########################################################################
#
# Copyright 2025 IHP PDK Authors
# 
# Licensed under the Apache License, Version 2.0 (the "License");
# you may not use this file except in compliance with the License.
# You may obtain a copy of the License at
# 
#    https://www.apache.org/licenses/LICENSE-2.0
# 
# Unless required by applicable law or agreed to in writing, software
# distributed under the License is distributed on an "AS IS" BASIS,
# WITHOUT WARRANTIES OR CONDITIONS OF ANY KIND, either express or implied.
# See the License for the specific language governing permissions and
# limitations under the License.
#
########################################################################

VERSION 5.7 ;
BUSBITCHARS "[]" ;
DIVIDERCHAR "/" ;

PROPERTYDEFINITIONS
  MACRO CatenaDesignType STRING ;
END PROPERTYDEFINITIONS

SITE  CoreSite
    CLASS       CORE ;
    SYMMETRY    Y ;
    SIZE        0.48 BY 3.78 ;
END  CoreSite

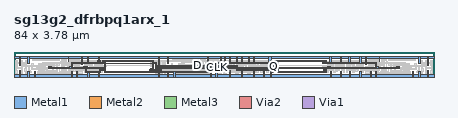
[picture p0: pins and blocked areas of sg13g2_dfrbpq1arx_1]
MACRO sg13g2_dfrbpq1arx_1
  CLASS CORE ;
  ORIGIN 0 0 ;
  FOREIGN sg13g2_dfrbpq1arx_1 0 0 ;
  SIZE 84 BY 3.78 ;
  SYMMETRY X Y ;
  SITE CoreSite ;
  PIN RESET_B
    DIRECTION INPUT ;
    USE SIGNAL ;
    ANTENNAPARTIALMETALAREA 7.2588 LAYER Metal3 ;
    ANTENNAPARTIALMETALAREA 0.605 LAYER Metal2 ;
    ANTENNAPARTIALCUTAREA 0.1444 LAYER Via1 ;
    ANTENNAPARTIALCUTAREA 0.1444 LAYER Via2 ;
    ANTENNAMODEL OXIDE1 ;
      ANTENNAGATEAREA 0.3276 LAYER Metal2 ;
      ANTENNAGATEAREA 0.3276 LAYER Metal1 ;
      ANTENNAGATEAREA 0.9828 LAYER Metal3 ;
      ANTENNAMAXAREACAR 12.730998 LAYER Metal3 ;
      ANTENNAMAXAREACAR 4.612561 LAYER Metal2 ;
      ANTENNAMAXCUTCAR 0.110195 LAYER Via1 ;
      ANTENNAMAXCUTCAR 0.550977 LAYER Via2 ;
    PORT
      LAYER Metal1 ;
        RECT 72.225 1.51 72.83 1.965 ;
        RECT 61.82 2.795 62.44 3.085 ;
        RECT 52.215 2.86 62.44 3.02 ;
        RECT 52.215 2.34 52.425 3.04 ;
        RECT 39.01 1.51 39.615 1.965 ;
        RECT 27.735 0.74 27.945 1.44 ;
        RECT 18.095 2.44 27.92 2.6 ;
        RECT 27.76 0.74 27.92 2.6 ;
        RECT 18.095 2.415 18.385 2.625 ;
        RECT 11.17 1.51 11.775 1.965 ;
      LAYER Metal2 ;
        RECT 71.88 2.42 72.58 2.62 ;
        RECT 72.38 1.535 72.58 2.62 ;
        RECT 61.82 2.795 62.44 3.085 ;
        RECT 61.775 2.42 62.065 3.04 ;
        RECT 52.22 2.34 52.42 3.04 ;
        RECT 51.72 2.42 52.42 2.62 ;
        RECT 39.26 2.42 39.96 2.62 ;
        RECT 39.26 0.74 39.46 2.62 ;
        RECT 38.76 0.74 39.46 0.94 ;
        RECT 27.74 0.74 28.44 0.94 ;
        RECT 27.74 0.74 27.94 1.44 ;
        RECT 17.18 2.42 18.385 2.62 ;
        RECT 16.7 2.84 17.38 3.04 ;
        RECT 17.18 2.42 17.38 3.04 ;
        RECT 16.7 2.42 16.9 3.04 ;
        RECT 16.2 2.42 16.9 2.62 ;
        RECT 11.42 2.42 12.12 2.62 ;
        RECT 11.42 1.535 11.62 2.62 ;
      LAYER Metal3 ;
        RECT 61.775 2.42 72.58 2.62 ;
        RECT 61.775 2.42 62.065 3.04 ;
        RECT 39.26 2.42 52.42 2.62 ;
        RECT 27.74 0.74 39.46 0.94 ;
        RECT 11.42 2.42 16.9 2.62 ;
      LAYER Via2 ;
        RECT 11.47 2.425 11.66 2.615 ;
        RECT 11.88 2.425 12.07 2.615 ;
        RECT 16.25 2.425 16.44 2.615 ;
        RECT 16.66 2.425 16.85 2.615 ;
        RECT 27.79 0.745 27.98 0.935 ;
        RECT 28.2 0.745 28.39 0.935 ;
        RECT 38.81 0.745 39 0.935 ;
        RECT 39.22 0.745 39.41 0.935 ;
        RECT 39.31 2.425 39.5 2.615 ;
        RECT 39.72 2.425 39.91 2.615 ;
        RECT 51.77 2.425 51.96 2.615 ;
        RECT 52.18 2.425 52.37 2.615 ;
        RECT 61.825 2.84 62.015 3.03 ;
        RECT 61.825 2.43 62.015 2.62 ;
        RECT 71.93 2.425 72.12 2.615 ;
        RECT 72.34 2.425 72.53 2.615 ;
      LAYER Via1 ;
        RECT 11.425 1.585 11.615 1.775 ;
        RECT 18.145 2.425 18.335 2.615 ;
        RECT 27.745 1.2 27.935 1.39 ;
        RECT 27.745 0.79 27.935 0.98 ;
        RECT 39.265 1.585 39.455 1.775 ;
        RECT 52.225 2.8 52.415 2.99 ;
        RECT 52.225 2.39 52.415 2.58 ;
        RECT 61.83 2.845 62.02 3.035 ;
        RECT 62.24 2.845 62.43 3.035 ;
        RECT 72.385 1.585 72.575 1.775 ;
    END
  END RESET_B
  PIN CLK
    DIRECTION INPUT ;
    USE SIGNAL ;
    ANTENNAPARTIALMETALAREA 8.124 LAYER Metal3 ;
    ANTENNAPARTIALMETALAREA 0.504 LAYER Metal2 ;
    ANTENNAPARTIALCUTAREA 0.1444 LAYER Via1 ;
    ANTENNAPARTIALCUTAREA 0.1444 LAYER Via2 ;
    ANTENNAMODEL OXIDE1 ;
      ANTENNAGATEAREA 0.2418 LAYER Metal2 ;
      ANTENNAGATEAREA 0.2418 LAYER Metal1 ;
      ANTENNAGATEAREA 0.7254 LAYER Metal3 ;
      ANTENNAMAXAREACAR 12.567411 LAYER Metal3 ;
      ANTENNAMAXAREACAR 0.74359 LAYER Metal2 ;
      ANTENNAMAXCUTCAR 0.149297 LAYER Via1 ;
      ANTENNAMAXCUTCAR 0.447891 LAYER Via2 ;
    PORT
      LAYER Metal1 ;
        RECT 76.53 1.52 77.07 1.84 ;
        RECT 61.815 0.7 62.025 1.4 ;
        RECT 52.695 0.76 62.025 0.92 ;
        RECT 52.695 0.7 52.905 1.4 ;
        RECT 34.77 1.52 35.31 1.84 ;
        RECT 27.695 2.835 27.985 3.045 ;
        RECT 18.14 2.86 27.985 3.02 ;
        RECT 18.14 2.86 18.43 3.09 ;
        RECT 6.93 1.52 7.47 1.84 ;
      LAYER Metal2 ;
        RECT 76.7 1.535 76.9 1.825 ;
        RECT 76.2 1.58 76.9 1.78 ;
        RECT 62.3 1.58 63 1.78 ;
        RECT 62.3 0.74 62.5 1.78 ;
        RECT 61.82 0.74 62.5 0.94 ;
        RECT 61.82 0.7 62.02 1.4 ;
        RECT 52.7 0.685 52.9 1.44 ;
        RECT 34.94 1.58 35.64 1.78 ;
        RECT 34.94 1.535 35.14 1.825 ;
        RECT 27.74 2.42 28.42 2.62 ;
        RECT 28.22 1.58 28.42 2.62 ;
        RECT 27.74 2.42 27.94 3.085 ;
        RECT 18.14 2.84 18.39 3.13 ;
        RECT 17.64 2.84 18.39 3.04 ;
        RECT 7.1 1.58 7.8 1.78 ;
        RECT 7.1 1.535 7.3 1.825 ;
      LAYER Metal3 ;
        RECT 62.3 1.58 76.9 1.78 ;
        RECT 28.22 1.58 52.9 1.78 ;
        RECT 52.7 0.74 52.9 1.78 ;
        RECT 28.22 1.58 28.42 2.28 ;
        RECT 17.64 2.84 18.34 3.04 ;
        RECT 18.14 1.58 18.34 3.04 ;
        RECT 7.1 1.58 18.34 1.78 ;
      LAYER Via2 ;
        RECT 7.15 1.585 7.34 1.775 ;
        RECT 7.56 1.585 7.75 1.775 ;
        RECT 17.69 2.845 17.88 3.035 ;
        RECT 18.1 2.845 18.29 3.035 ;
        RECT 28.225 2.04 28.415 2.23 ;
        RECT 28.225 1.63 28.415 1.82 ;
        RECT 34.99 1.585 35.18 1.775 ;
        RECT 35.4 1.585 35.59 1.775 ;
        RECT 52.705 1.2 52.895 1.39 ;
        RECT 52.705 0.79 52.895 0.98 ;
        RECT 62.35 1.585 62.54 1.775 ;
        RECT 62.76 1.585 62.95 1.775 ;
        RECT 76.25 1.585 76.44 1.775 ;
        RECT 76.66 1.585 76.85 1.775 ;
      LAYER Via1 ;
        RECT 7.105 1.585 7.295 1.775 ;
        RECT 18.19 2.89 18.38 3.08 ;
        RECT 27.745 2.845 27.935 3.035 ;
        RECT 34.945 1.585 35.135 1.775 ;
        RECT 52.705 1.16 52.895 1.35 ;
        RECT 52.705 0.75 52.895 0.94 ;
        RECT 61.825 1.16 62.015 1.35 ;
        RECT 61.825 0.75 62.015 0.94 ;
        RECT 76.705 1.585 76.895 1.775 ;
    END
  END CLK
  PIN VSS
    DIRECTION INOUT ;
    USE GROUND ;
    SHAPE ABUTMENT ;
    NETEXPR "VSS VSS!" ;
    PORT
      LAYER Metal1 ;
        RECT 0 -0.22 84 0.22 ;
        RECT 82.715 -0.22 82.975 1.19 ;
        RECT 80.99 -0.22 81.23 0.85 ;
        RECT 79.64 -0.22 79.9 0.85 ;
        RECT 72.315 -0.22 72.575 0.915 ;
        RECT 71.22 -0.22 71.49 0.85 ;
        RECT 69.155 -0.22 69.415 0.87 ;
        RECT 67.1 -0.22 67.36 0.87 ;
        RECT 65.315 -0.22 65.575 0.87 ;
        RECT 63.26 -0.22 63.52 0.87 ;
        RECT 51.215 -0.22 51.475 0.87 ;
        RECT 49.855 -0.22 50.115 0.87 ;
        RECT 47.825 -0.22 48.085 1.155 ;
        RECT 45.425 -0.22 45.685 1.155 ;
        RECT 43.025 -0.22 43.285 1.155 ;
        RECT 40.35 -0.22 40.62 0.85 ;
        RECT 39.265 -0.22 39.525 0.915 ;
        RECT 31.94 -0.22 32.2 0.85 ;
        RECT 30.61 -0.22 30.85 0.85 ;
        RECT 28.865 -0.22 29.125 1.19 ;
        RECT 16.835 -0.22 17.095 0.87 ;
        RECT 14.78 -0.22 15.04 0.87 ;
        RECT 12.51 -0.22 12.78 0.85 ;
        RECT 11.425 -0.22 11.685 0.915 ;
        RECT 4.1 -0.22 4.36 0.85 ;
        RECT 2.77 -0.22 3.01 0.85 ;
        RECT 1.025 -0.22 1.285 1.19 ;
    END
  END VSS
  PIN VDD
    DIRECTION INOUT ;
    USE POWER ;
    SHAPE ABUTMENT ;
    NETEXPR "VDD VDD!" ;
    PORT
      LAYER Metal1 ;
        RECT 0 3.56 84 4 ;
        RECT 82.71 2.1 82.98 4 ;
        RECT 80.97 2.46 81.23 4 ;
        RECT 73.025 2.86 73.195 4 ;
        RECT 70.295 2.24 70.555 4 ;
        RECT 69.14 2.455 69.4 4 ;
        RECT 66.985 2.65 67.25 4 ;
        RECT 65.3 2.455 65.56 4 ;
        RECT 63.145 2.65 63.41 4 ;
        RECT 50.81 2.475 51.41 4 ;
        RECT 47.825 2.56 48.085 4 ;
        RECT 46.805 2.56 47.065 4 ;
        RECT 45.425 2.56 45.685 4 ;
        RECT 44.405 2.56 44.665 4 ;
        RECT 43.025 2.56 43.285 4 ;
        RECT 42.005 2.56 42.265 4 ;
        RECT 41.285 2.24 41.545 4 ;
        RECT 38.645 2.86 38.815 4 ;
        RECT 30.61 2.46 30.87 4 ;
        RECT 28.86 2.1 29.13 4 ;
        RECT 16.82 2.455 17.08 4 ;
        RECT 14.665 2.65 14.93 4 ;
        RECT 13.445 2.24 13.705 4 ;
        RECT 10.805 2.86 10.975 4 ;
        RECT 2.77 2.46 3.03 4 ;
        RECT 1.02 2.1 1.29 4 ;
    END
  END VDD
  PIN D
    DIRECTION INPUT ;
    USE SIGNAL ;
    ANTENNAPARTIALMETALAREA 5.597 LAYER Metal3 ;
    ANTENNAPARTIALCUTAREA 0.1444 LAYER Via1 ;
    ANTENNAPARTIALCUTAREA 0.1444 LAYER Via2 ;
    ANTENNAMODEL OXIDE1 ;
      ANTENNAGATEAREA 0.1092 LAYER Metal2 ;
      ANTENNAGATEAREA 0.1092 LAYER Metal1 ;
      ANTENNAGATEAREA 0.3276 LAYER Metal3 ;
      ANTENNAMAXAREACAR 39.387057 LAYER Metal3 ;
      ANTENNAMAXAREACAR 18.283883 LAYER Metal2 ;
      ANTENNAMAXCUTCAR 0.661172 LAYER Via1 ;
      ANTENNAMAXCUTCAR 1.322344 LAYER Via2 ;
    PORT
      LAYER Metal1 ;
        RECT 62.605 1.425 63.235 1.945 ;
        RECT 52.215 1.6 63.235 1.76 ;
        RECT 52.215 1.08 52.425 1.78 ;
        RECT 41.16 1.07 41.505 1.89 ;
        RECT 27.17 0.74 27.46 1.36 ;
        RECT 18.135 0.76 27.46 0.92 ;
        RECT 18.135 0.74 18.345 1.44 ;
        RECT 14.125 1.425 14.755 1.945 ;
        RECT 13.88 1.535 14.755 1.825 ;
      LAYER Metal2 ;
        RECT 52.22 1.08 52.42 1.78 ;
        RECT 51.26 1.16 52.42 1.36 ;
        RECT 44.495 1.16 44.785 1.36 ;
        RECT 44.04 2 44.74 2.2 ;
        RECT 44.54 1.16 44.74 2.2 ;
        RECT 41.18 2 41.88 2.2 ;
        RECT 41.18 1.16 41.38 2.2 ;
        RECT 28.7 2 29.4 2.2 ;
        RECT 28.7 1.16 29.4 1.36 ;
        RECT 28.7 1.16 28.9 2.2 ;
        RECT 27.26 0.66 27.46 1.415 ;
        RECT 27.21 0.7 27.46 1.4 ;
        RECT 17.66 1.16 18.36 1.36 ;
        RECT 18.14 0.74 18.34 1.44 ;
        RECT 14.3 0.74 15 0.94 ;
        RECT 13.88 1.535 14.5 1.825 ;
        RECT 14.3 0.74 14.5 1.825 ;
      LAYER Metal3 ;
        RECT 44.495 1.16 51.96 1.36 ;
        RECT 28.7 2 44.74 2.2 ;
        RECT 27.26 1.16 29.4 1.36 ;
        RECT 27.26 0.66 27.46 1.36 ;
        RECT 17.18 1.16 18.36 1.36 ;
        RECT 17.18 0.74 17.38 1.36 ;
        RECT 14.3 0.74 17.38 0.94 ;
      LAYER Via2 ;
        RECT 14.35 0.745 14.54 0.935 ;
        RECT 14.76 0.745 14.95 0.935 ;
        RECT 17.71 1.165 17.9 1.355 ;
        RECT 18.12 1.165 18.31 1.355 ;
        RECT 27.265 1.12 27.455 1.31 ;
        RECT 27.265 0.71 27.455 0.9 ;
        RECT 28.75 2.005 28.94 2.195 ;
        RECT 28.75 1.165 28.94 1.355 ;
        RECT 29.16 2.005 29.35 2.195 ;
        RECT 29.16 1.165 29.35 1.355 ;
        RECT 41.23 2.005 41.42 2.195 ;
        RECT 41.64 2.005 41.83 2.195 ;
        RECT 44.09 2.005 44.28 2.195 ;
        RECT 44.5 2.005 44.69 2.195 ;
        RECT 44.545 1.165 44.735 1.355 ;
        RECT 51.31 1.165 51.5 1.355 ;
        RECT 51.72 1.165 51.91 1.355 ;
      LAYER Via1 ;
        RECT 13.89 1.585 14.08 1.775 ;
        RECT 14.3 1.585 14.49 1.775 ;
        RECT 18.145 1.2 18.335 1.39 ;
        RECT 18.145 0.79 18.335 0.98 ;
        RECT 27.22 1.16 27.41 1.35 ;
        RECT 27.22 0.75 27.41 0.94 ;
        RECT 41.185 1.62 41.375 1.81 ;
        RECT 41.185 1.21 41.375 1.4 ;
        RECT 52.225 1.54 52.415 1.73 ;
        RECT 52.225 1.13 52.415 1.32 ;
    END
  END D
  PIN Q
    DIRECTION OUTPUT ;
    USE SIGNAL ;
    ANTENNAPARTIALCUTAREA 0.0361 LAYER Via1 ;
    ANTENNAPARTIALCUTAREA 0.0722 LAYER Via2 ;
    ANTENNADIFFAREA 0.6324 LAYER Metal2 ;
    ANTENNADIFFAREA 0.6324 LAYER Metal1 ;
    ANTENNADIFFAREA 0.6324 LAYER Metal3 ;
    PORT
      LAYER Metal1 ;
        RECT 51.65 2.86 52.01 3.16 ;
        RECT 51.85 0.605 52.01 3.16 ;
        RECT 51.66 2.22 52.01 3.16 ;
        RECT 51.72 0.605 52.01 1.215 ;
      LAYER Metal2 ;
        RECT 51.26 2.84 51.96 3.04 ;
        RECT 51.69 2.84 51.94 3.13 ;
      LAYER Metal3 ;
        RECT 51.26 2.84 52.46 3.04 ;
      LAYER Via2 ;
        RECT 51.31 2.845 51.5 3.035 ;
        RECT 51.72 2.845 51.91 3.035 ;
      LAYER Via1 ;
        RECT 51.7 2.89 51.89 3.08 ;
    END
  END Q
  OBS
    LAYER Metal1 ;
      RECT 83.225 2.095 83.64 3.155 ;
      RECT 83.43 0.59 83.64 3.155 ;
      RECT 83.415 1.92 83.64 3.155 ;
      RECT 83.205 0.59 83.64 1.19 ;
      RECT 82.205 0.59 82.465 3.155 ;
      RECT 82.95 1.445 83.25 1.745 ;
      RECT 82.205 1.485 83.25 1.71 ;
      RECT 81.48 0.59 81.74 3.155 ;
      RECT 81.42 0.99 81.805 1.52 ;
      RECT 80.15 2.035 80.41 2.495 ;
      RECT 79.3 2.035 81.08 2.195 ;
      RECT 80.92 1.03 81.08 2.195 ;
      RECT 79.3 1.69 79.56 2.195 ;
      RECT 80.65 1.03 81.08 1.19 ;
      RECT 80.65 0.625 80.81 1.19 ;
      RECT 80.46 0.625 80.81 0.885 ;
      RECT 78.555 2.225 79.03 2.485 ;
      RECT 78.87 1.145 79.03 2.485 ;
      RECT 80.245 1.35 80.55 1.625 ;
      RECT 78.87 1.35 80.55 1.51 ;
      RECT 78.87 1.145 79.05 1.51 ;
      RECT 78.04 1.145 79.05 1.315 ;
      RECT 79.99 3.025 80.24 3.285 ;
      RECT 74.935 3.025 75.195 3.285 ;
      RECT 74.935 3.075 80.24 3.235 ;
      RECT 77.59 0.805 77.805 1.31 ;
      RECT 77.59 0.805 79.39 0.965 ;
      RECT 79.13 0.59 79.39 0.965 ;
      RECT 71.28 2.5 72.02 2.76 ;
      RECT 71.28 1.15 71.44 2.76 ;
      RECT 77.825 1.555 78.015 2.425 ;
      RECT 73.03 1.705 73.29 1.965 ;
      RECT 77.25 1.555 78.015 1.725 ;
      RECT 73.03 1.15 73.19 1.965 ;
      RECT 77.25 0.44 77.41 1.725 ;
      RECT 71.28 1.15 73.19 1.31 ;
      RECT 72.785 0.44 72.955 1.31 ;
      RECT 71.8 0.815 72.06 1.31 ;
      RECT 78.62 0.44 78.88 0.625 ;
      RECT 72.785 0.44 78.88 0.605 ;
      RECT 75.63 2.63 78.355 2.8 ;
      RECT 78.195 1.525 78.355 2.8 ;
      RECT 75.63 2.07 75.89 2.8 ;
      RECT 74.935 2.16 75.89 2.42 ;
      RECT 75.225 2.07 75.89 2.42 ;
      RECT 75.225 0.92 75.5 2.42 ;
      RECT 78.195 1.525 78.68 1.785 ;
      RECT 75.225 0.92 75.895 1.18 ;
      RECT 76.1 2.07 77.605 2.33 ;
      RECT 76.1 0.98 76.26 2.33 ;
      RECT 75.805 1.575 76.26 1.835 ;
      RECT 76.835 0.92 77.07 1.18 ;
      RECT 76.1 0.98 77.07 1.14 ;
      RECT 74.74 1.44 74.985 1.7 ;
      RECT 74.805 0.785 74.985 1.7 ;
      RECT 73.2 0.785 74.985 0.96 ;
      RECT 73.445 3.08 74.585 3.24 ;
      RECT 74.4 2.655 74.585 3.24 ;
      RECT 70.865 3.08 72.845 3.24 ;
      RECT 72.685 2.52 72.845 3.24 ;
      RECT 73.445 2.52 73.615 3.24 ;
      RECT 70.865 0.59 71.03 3.24 ;
      RECT 74.4 2.655 74.745 2.915 ;
      RECT 72.685 2.52 73.615 2.68 ;
      RECT 74.4 1.16 74.56 3.24 ;
      RECT 70.8 2.24 71.06 2.5 ;
      RECT 73.465 1.16 73.725 1.64 ;
      RECT 73.465 1.16 74.56 1.32 ;
      RECT 70.29 0.59 71.03 0.85 ;
      RECT 72.325 2.145 72.505 2.9 ;
      RECT 73.975 1.5 74.195 2.805 ;
      RECT 72.325 2.145 74.195 2.315 ;
      RECT 71.665 2.145 74.195 2.305 ;
      RECT 71.665 1.705 71.925 2.305 ;
      RECT 69.67 2.22 69.925 3.16 ;
      RECT 69.735 0.61 69.925 3.16 ;
      RECT 70.335 1.07 70.68 1.89 ;
      RECT 69.305 1.115 69.925 1.37 ;
      RECT 69.665 0.61 69.925 1.37 ;
      RECT 69.305 1.18 70.68 1.34 ;
      RECT 68.405 2.03 68.665 3.04 ;
      RECT 68.405 2.03 69.445 2.205 ;
      RECT 69.285 1.55 69.445 2.205 ;
      RECT 68.82 1.55 69.555 1.81 ;
      RECT 68.82 1.16 68.98 1.81 ;
      RECT 68.395 1.16 68.98 1.36 ;
      RECT 68.395 0.96 68.635 1.36 ;
      RECT 67.76 2.615 68.065 2.945 ;
      RECT 67.82 1.555 68.065 2.945 ;
      RECT 67.82 1.555 68.64 1.815 ;
      RECT 67.82 0.61 68.05 2.945 ;
      RECT 67.76 0.61 68.05 0.87 ;
      RECT 66.48 2.195 66.74 2.91 ;
      RECT 66.48 2.195 67.615 2.4 ;
      RECT 67.36 1.065 67.615 2.4 ;
      RECT 66.45 1.065 67.615 1.24 ;
      RECT 66.45 0.61 66.72 1.24 ;
      RECT 65.83 2.22 66.085 3.16 ;
      RECT 65.895 0.61 66.085 3.16 ;
      RECT 65.465 1.115 66.085 1.37 ;
      RECT 65.825 0.61 66.085 1.37 ;
      RECT 64.565 2.03 64.825 3.04 ;
      RECT 64.565 2.03 65.605 2.205 ;
      RECT 65.445 1.55 65.605 2.205 ;
      RECT 64.98 1.55 65.715 1.81 ;
      RECT 64.98 1.16 65.14 1.81 ;
      RECT 64.555 1.16 65.14 1.36 ;
      RECT 64.555 0.96 64.795 1.36 ;
      RECT 63.92 2.615 64.225 2.945 ;
      RECT 63.98 1.555 64.225 2.945 ;
      RECT 63.98 1.555 64.8 1.815 ;
      RECT 63.98 0.61 64.21 2.945 ;
      RECT 63.92 0.61 64.21 0.87 ;
      RECT 62.64 2.195 62.9 2.91 ;
      RECT 62.64 2.195 63.775 2.4 ;
      RECT 63.52 1.065 63.775 2.4 ;
      RECT 62.61 1.065 63.775 1.24 ;
      RECT 62.61 0.61 62.88 1.24 ;
      RECT 52.695 1.96 52.905 2.66 ;
      RECT 52.695 2.02 62.02 2.18 ;
      RECT 61.73 1.95 62.02 2.18 ;
      RECT 49.345 2.09 49.605 3.04 ;
      RECT 49.345 2.09 51.475 2.295 ;
      RECT 51.305 1.115 51.475 2.295 ;
      RECT 51.305 1.52 51.67 1.85 ;
      RECT 49.345 1.115 51.475 1.325 ;
      RECT 49.345 1.11 50.925 1.325 ;
      RECT 50.405 0.61 50.925 1.325 ;
      RECT 49.345 0.61 49.605 1.325 ;
      RECT 48.335 2.14 48.835 3.16 ;
      RECT 48.6 0.72 48.835 3.16 ;
      RECT 48.335 0.72 48.835 1.36 ;
      RECT 47.315 2.05 47.575 3.16 ;
      RECT 46.805 2.05 48.12 2.24 ;
      RECT 47.96 1.605 48.12 2.24 ;
      RECT 46.805 1.14 47.065 2.24 ;
      RECT 47.96 1.605 48.3 1.865 ;
      RECT 46.665 0.735 47.64 0.96 ;
      RECT 46.665 0.405 47.34 0.96 ;
      RECT 45.935 2.14 46.435 3.16 ;
      RECT 46.2 0.72 46.435 3.16 ;
      RECT 45.935 2.375 46.6 2.665 ;
      RECT 45.935 0.72 46.435 1.32 ;
      RECT 44.915 2.05 45.175 3.16 ;
      RECT 44.405 2.05 45.72 2.24 ;
      RECT 45.56 1.605 45.72 2.24 ;
      RECT 44.405 1.14 44.665 2.24 ;
      RECT 45.56 1.605 45.9 1.865 ;
      RECT 44.265 0.735 45.24 0.96 ;
      RECT 44.265 0.405 44.94 0.96 ;
      RECT 43.535 2.14 44.035 3.16 ;
      RECT 43.8 0.72 44.035 3.16 ;
      RECT 43.535 2.795 44.2 3.085 ;
      RECT 43.535 0.72 44.035 1.32 ;
      RECT 42.515 2.05 42.775 3.16 ;
      RECT 42.005 2.05 43.32 2.24 ;
      RECT 43.16 1.605 43.32 2.24 ;
      RECT 42.005 1.14 42.265 2.24 ;
      RECT 43.16 1.605 43.5 1.865 ;
      RECT 41.865 0.735 42.84 0.96 ;
      RECT 41.865 0.405 42.54 0.96 ;
      RECT 38.995 3.08 40.975 3.24 ;
      RECT 40.81 0.59 40.975 3.24 ;
      RECT 37.255 3.08 38.395 3.24 ;
      RECT 38.225 2.52 38.395 3.24 ;
      RECT 38.995 2.52 39.155 3.24 ;
      RECT 37.255 2.655 37.44 3.24 ;
      RECT 37.28 1.16 37.44 3.24 ;
      RECT 37.095 2.655 37.44 2.915 ;
      RECT 38.225 2.52 39.155 2.68 ;
      RECT 40.78 2.24 41.04 2.5 ;
      RECT 38.115 1.16 38.375 1.64 ;
      RECT 37.28 1.16 38.375 1.32 ;
      RECT 40.81 0.59 41.55 0.85 ;
      RECT 39.82 2.5 40.56 2.76 ;
      RECT 40.4 1.15 40.56 2.76 ;
      RECT 33.825 1.555 34.015 2.425 ;
      RECT 38.55 1.705 38.81 1.965 ;
      RECT 38.65 1.15 38.81 1.965 ;
      RECT 33.825 1.555 34.59 1.725 ;
      RECT 34.43 0.44 34.59 1.725 ;
      RECT 38.65 1.15 40.56 1.31 ;
      RECT 39.78 0.815 40.04 1.31 ;
      RECT 38.885 0.44 39.055 1.31 ;
      RECT 32.96 0.44 33.22 0.625 ;
      RECT 32.96 0.44 39.055 0.605 ;
      RECT 39.335 2.145 39.515 2.9 ;
      RECT 37.645 1.5 37.865 2.805 ;
      RECT 37.645 2.145 39.515 2.315 ;
      RECT 37.645 2.145 40.175 2.305 ;
      RECT 39.915 1.705 40.175 2.305 ;
      RECT 36.855 1.44 37.1 1.7 ;
      RECT 36.855 0.785 37.035 1.7 ;
      RECT 36.855 0.785 38.64 0.96 ;
      RECT 33.485 2.63 36.21 2.8 ;
      RECT 35.95 2.07 36.21 2.8 ;
      RECT 33.485 1.525 33.645 2.8 ;
      RECT 35.95 2.16 36.905 2.42 ;
      RECT 35.95 2.07 36.615 2.42 ;
      RECT 36.34 0.92 36.615 2.42 ;
      RECT 33.16 1.525 33.645 1.785 ;
      RECT 35.945 0.92 36.615 1.18 ;
      RECT 36.645 3.025 36.905 3.285 ;
      RECT 31.6 3.025 31.85 3.285 ;
      RECT 31.6 3.075 36.905 3.235 ;
      RECT 34.235 2.07 35.74 2.33 ;
      RECT 35.58 0.98 35.74 2.33 ;
      RECT 35.58 1.575 36.035 1.835 ;
      RECT 34.77 0.92 35.005 1.18 ;
      RECT 34.77 0.98 35.74 1.14 ;
      RECT 34.035 0.805 34.25 1.31 ;
      RECT 32.45 0.805 34.25 0.965 ;
      RECT 32.45 0.59 32.71 0.965 ;
      RECT 32.81 2.225 33.285 2.485 ;
      RECT 32.81 1.145 32.97 2.485 ;
      RECT 31.29 1.35 31.595 1.625 ;
      RECT 31.29 1.35 32.97 1.51 ;
      RECT 32.79 1.145 32.97 1.51 ;
      RECT 32.79 1.145 33.8 1.315 ;
      RECT 31.43 2.035 31.69 2.495 ;
      RECT 30.76 2.035 32.54 2.195 ;
      RECT 32.28 1.69 32.54 2.195 ;
      RECT 30.76 1.03 30.92 2.195 ;
      RECT 30.76 1.03 31.19 1.19 ;
      RECT 31.03 0.625 31.19 1.19 ;
      RECT 31.03 0.625 31.38 0.885 ;
      RECT 30.1 0.59 30.36 3.155 ;
      RECT 30.035 0.99 30.42 1.52 ;
      RECT 29.375 0.59 29.635 3.155 ;
      RECT 28.59 1.445 28.89 1.745 ;
      RECT 28.59 1.485 29.635 1.71 ;
      RECT 28.2 2.095 28.615 3.155 ;
      RECT 28.175 2.835 28.615 3.045 ;
      RECT 28.2 0.59 28.41 3.155 ;
      RECT 28.2 0.59 28.635 1.19 ;
      RECT 27.215 1.995 27.505 2.205 ;
      RECT 18.14 2.02 27.505 2.18 ;
      RECT 18.14 1.95 18.43 2.18 ;
      RECT 17.35 2.22 17.605 3.16 ;
      RECT 17.415 0.61 17.605 3.16 ;
      RECT 16.985 1.115 17.605 1.37 ;
      RECT 17.345 0.61 17.605 1.37 ;
      RECT 16.085 2.03 16.345 3.04 ;
      RECT 16.085 2.03 17.125 2.205 ;
      RECT 16.965 1.55 17.125 2.205 ;
      RECT 16.5 1.55 17.235 1.81 ;
      RECT 16.5 1.16 16.66 1.81 ;
      RECT 16.075 1.16 16.66 1.36 ;
      RECT 16.075 0.96 16.315 1.36 ;
      RECT 15.44 2.615 15.745 2.945 ;
      RECT 15.5 1.555 15.745 2.945 ;
      RECT 15.5 1.555 16.32 1.815 ;
      RECT 15.5 0.61 15.73 2.945 ;
      RECT 15.44 0.61 15.73 0.87 ;
      RECT 14.16 2.195 14.42 2.91 ;
      RECT 14.16 2.195 15.295 2.4 ;
      RECT 15.04 1.065 15.295 2.4 ;
      RECT 14.13 1.065 15.295 1.24 ;
      RECT 14.13 0.61 14.4 1.24 ;
      RECT 11.155 3.08 13.135 3.24 ;
      RECT 12.97 0.59 13.135 3.24 ;
      RECT 9.415 3.08 10.555 3.24 ;
      RECT 10.385 2.52 10.555 3.24 ;
      RECT 11.155 2.52 11.315 3.24 ;
      RECT 9.415 2.655 9.6 3.24 ;
      RECT 9.44 1.16 9.6 3.24 ;
      RECT 9.255 2.655 9.6 2.915 ;
      RECT 10.385 2.52 11.315 2.68 ;
      RECT 12.94 2.24 13.2 2.5 ;
      RECT 10.275 1.16 10.535 1.64 ;
      RECT 9.44 1.16 10.535 1.32 ;
      RECT 12.97 0.59 13.71 0.85 ;
      RECT 11.98 2.5 12.72 2.76 ;
      RECT 12.56 1.15 12.72 2.76 ;
      RECT 5.985 1.555 6.175 2.425 ;
      RECT 10.71 1.705 10.97 1.965 ;
      RECT 10.81 1.15 10.97 1.965 ;
      RECT 5.985 1.555 6.75 1.725 ;
      RECT 6.59 0.44 6.75 1.725 ;
      RECT 10.81 1.15 12.72 1.31 ;
      RECT 11.94 0.815 12.2 1.31 ;
      RECT 11.045 0.44 11.215 1.31 ;
      RECT 5.12 0.44 5.38 0.625 ;
      RECT 5.12 0.44 11.215 0.605 ;
      RECT 11.495 2.145 11.675 2.9 ;
      RECT 9.805 1.5 10.025 2.805 ;
      RECT 9.805 2.145 11.675 2.315 ;
      RECT 9.805 2.145 12.335 2.305 ;
      RECT 12.075 1.705 12.335 2.305 ;
      RECT 9.015 1.44 9.26 1.7 ;
      RECT 9.015 0.785 9.195 1.7 ;
      RECT 9.015 0.785 10.8 0.96 ;
      RECT 5.645 2.63 8.37 2.8 ;
      RECT 8.11 2.07 8.37 2.8 ;
      RECT 5.645 1.525 5.805 2.8 ;
      RECT 8.11 2.16 9.065 2.42 ;
      RECT 8.11 2.07 8.775 2.42 ;
      RECT 8.5 0.92 8.775 2.42 ;
      RECT 5.32 1.525 5.805 1.785 ;
      RECT 8.105 0.92 8.775 1.18 ;
      RECT 8.805 3.025 9.065 3.285 ;
      RECT 3.76 3.025 4.01 3.285 ;
      RECT 3.76 3.075 9.065 3.235 ;
      RECT 6.395 2.07 7.9 2.33 ;
      RECT 7.74 0.98 7.9 2.33 ;
      RECT 7.74 1.575 8.195 1.835 ;
      RECT 6.93 0.92 7.165 1.18 ;
      RECT 6.93 0.98 7.9 1.14 ;
      RECT 6.195 0.805 6.41 1.31 ;
      RECT 4.61 0.805 6.41 0.965 ;
      RECT 4.61 0.59 4.87 0.965 ;
      RECT 4.97 2.225 5.445 2.485 ;
      RECT 4.97 1.145 5.13 2.485 ;
      RECT 3.45 1.35 3.755 1.625 ;
      RECT 3.45 1.35 5.13 1.51 ;
      RECT 4.95 1.145 5.13 1.51 ;
      RECT 4.95 1.145 5.96 1.315 ;
      RECT 3.59 2.035 3.85 2.495 ;
      RECT 2.92 2.035 4.7 2.195 ;
      RECT 4.44 1.69 4.7 2.195 ;
      RECT 2.92 1.03 3.08 2.195 ;
      RECT 2.92 1.03 3.35 1.19 ;
      RECT 3.19 0.625 3.35 1.19 ;
      RECT 3.19 0.625 3.54 0.885 ;
      RECT 2.26 0.59 2.52 3.155 ;
      RECT 2.195 0.99 2.58 1.52 ;
      RECT 1.535 0.59 1.795 3.155 ;
      RECT 0.75 1.445 1.05 1.745 ;
      RECT 0.75 1.485 1.795 1.71 ;
      RECT 0.36 2.095 0.775 3.155 ;
      RECT 0.36 1.92 0.63 3.155 ;
      RECT 0.36 0.59 0.57 3.155 ;
      RECT 0.36 0.59 0.795 1.19 ;
      RECT 66.445 1.425 67.075 1.945 ;
      RECT 50.7 1.505 51.03 1.9 ;
      RECT 50.05 1.505 50.52 1.9 ;
      RECT 49.255 1.505 49.795 1.9 ;
      RECT 47.34 1.435 47.73 1.87 ;
      RECT 44.94 1.435 45.33 1.87 ;
      RECT 42.54 1.435 42.93 1.87 ;
      RECT 13.32 1.07 13.665 1.89 ;
    LAYER Via1 ;
      RECT 83.425 1.97 83.615 2.16 ;
      RECT 83.425 2.38 83.615 2.57 ;
      RECT 66.625 1.585 66.815 1.775 ;
      RECT 65.665 1.165 65.855 1.355 ;
      RECT 61.78 1.96 61.97 2.15 ;
      RECT 52.705 2.01 52.895 2.2 ;
      RECT 52.705 2.42 52.895 2.61 ;
      RECT 50.785 1.585 50.975 1.775 ;
      RECT 50.305 1.585 50.495 1.775 ;
      RECT 49.345 1.585 49.535 1.775 ;
      RECT 48.385 0.75 48.575 0.94 ;
      RECT 48.385 1.16 48.575 1.35 ;
      RECT 47.425 1.585 47.615 1.775 ;
      RECT 47.4 0.745 47.59 0.935 ;
      RECT 46.99 0.745 47.18 0.935 ;
      RECT 46.4 2.425 46.59 2.615 ;
      RECT 45.99 2.425 46.18 2.615 ;
      RECT 45.025 1.585 45.215 1.775 ;
      RECT 45 0.745 45.19 0.935 ;
      RECT 44.59 0.745 44.78 0.935 ;
      RECT 44 2.845 44.19 3.035 ;
      RECT 43.59 2.845 43.78 3.035 ;
      RECT 42.625 1.585 42.815 1.775 ;
      RECT 42.6 0.745 42.79 0.935 ;
      RECT 42.19 0.745 42.38 0.935 ;
      RECT 28.225 2.845 28.415 3.035 ;
      RECT 27.265 2.005 27.455 2.195 ;
      RECT 18.19 1.96 18.38 2.15 ;
      RECT 17.185 1.165 17.375 1.355 ;
      RECT 13.345 1.21 13.535 1.4 ;
      RECT 13.345 1.62 13.535 1.81 ;
      RECT 0.385 1.97 0.575 2.16 ;
      RECT 0.385 2.38 0.575 2.57 ;
    LAYER Metal2 ;
      RECT 82.92 2.42 83.62 2.62 ;
      RECT 83.42 1.92 83.62 2.62 ;
      RECT 65.66 1.58 66.865 1.78 ;
      RECT 65.66 1.115 65.86 1.78 ;
      RECT 63.26 2.84 63.96 3.04 ;
      RECT 63.26 2 63.46 3.04 ;
      RECT 62.76 2 63.46 2.2 ;
      RECT 61.77 2 62.52 2.2 ;
      RECT 61.77 1.655 62.02 2.2 ;
      RECT 50.28 2.84 50.98 3.04 ;
      RECT 50.78 1.535 50.98 3.04 ;
      RECT 45.98 2.375 46.6 2.665 ;
      RECT 45.98 2.42 50.5 2.62 ;
      RECT 50.3 1.535 50.5 2.62 ;
      RECT 48.38 1.58 49.585 1.78 ;
      RECT 48.38 0.7 48.58 1.78 ;
      RECT 47.42 2 48.12 2.2 ;
      RECT 47.42 1.535 47.62 2.2 ;
      RECT 45.02 1.535 45.22 1.825 ;
      RECT 45.02 1.58 47.62 1.78 ;
      RECT 41.64 1.16 42.34 1.36 ;
      RECT 42.14 0.74 42.34 1.36 ;
      RECT 42.14 0.74 45.24 0.94 ;
      RECT 43.58 2.795 44.2 3.085 ;
      RECT 43.58 2.84 45.24 3.04 ;
      RECT 42.12 2.84 42.82 3.04 ;
      RECT 42.62 1.16 42.82 3.04 ;
      RECT 42.62 1.16 44.28 1.36 ;
      RECT 28.175 2.84 29.86 3.04 ;
      RECT 29.66 1.16 29.86 3.04 ;
      RECT 29.66 1.16 30.36 1.36 ;
      RECT 17.18 2 18.39 2.2 ;
      RECT 18.14 1.91 18.39 2.2 ;
      RECT 17.18 1.115 17.38 1.405 ;
      RECT 16.2 1.16 17.38 1.36 ;
      RECT 13.34 1.16 13.54 1.86 ;
      RECT 12.84 1.16 13.54 1.36 ;
      RECT 0.38 2.42 1.08 2.62 ;
      RECT 0.38 1.92 0.58 2.62 ;
      RECT 52.7 1.96 52.9 2.7 ;
      RECT 46.44 0.74 47.64 0.94 ;
      RECT 27.26 1.955 27.46 3.04 ;
    LAYER Via2 ;
      RECT 83.38 2.425 83.57 2.615 ;
      RECT 82.97 2.425 83.16 2.615 ;
      RECT 63.72 2.845 63.91 3.035 ;
      RECT 63.31 2.845 63.5 3.035 ;
      RECT 63.22 2.005 63.41 2.195 ;
      RECT 62.81 2.005 63 2.195 ;
      RECT 62.28 2.005 62.47 2.195 ;
      RECT 61.87 2.005 62.06 2.195 ;
      RECT 52.705 2.05 52.895 2.24 ;
      RECT 52.705 2.46 52.895 2.65 ;
      RECT 50.74 2.845 50.93 3.035 ;
      RECT 50.33 2.845 50.52 3.035 ;
      RECT 47.88 2.005 48.07 2.195 ;
      RECT 47.47 2.005 47.66 2.195 ;
      RECT 46.9 0.745 47.09 0.935 ;
      RECT 46.49 0.745 46.68 0.935 ;
      RECT 45 2.845 45.19 3.035 ;
      RECT 44.59 2.845 44.78 3.035 ;
      RECT 44.04 1.165 44.23 1.355 ;
      RECT 43.63 1.165 43.82 1.355 ;
      RECT 42.58 2.845 42.77 3.035 ;
      RECT 42.17 2.845 42.36 3.035 ;
      RECT 42.1 1.165 42.29 1.355 ;
      RECT 41.69 1.165 41.88 1.355 ;
      RECT 30.12 1.165 30.31 1.355 ;
      RECT 29.71 1.165 29.9 1.355 ;
      RECT 27.265 2.39 27.455 2.58 ;
      RECT 27.265 2.8 27.455 2.99 ;
      RECT 17.64 2.005 17.83 2.195 ;
      RECT 17.23 2.005 17.42 2.195 ;
      RECT 16.66 1.165 16.85 1.355 ;
      RECT 16.25 1.165 16.44 1.355 ;
      RECT 13.3 1.165 13.49 1.355 ;
      RECT 12.89 1.165 13.08 1.355 ;
      RECT 0.84 2.425 1.03 2.615 ;
      RECT 0.43 2.425 0.62 2.615 ;
    LAYER Metal3 ;
      RECT 63.26 2.84 73.06 3.04 ;
      RECT 72.86 2.42 73.06 3.04 ;
      RECT 81.98 2.42 83.62 2.62 ;
      RECT 72.86 2.42 77.86 2.62 ;
      RECT 77.66 2 77.86 2.62 ;
      RECT 81.98 2 82.18 2.62 ;
      RECT 77.66 2 82.18 2.2 ;
      RECT 52.7 2 52.9 2.7 ;
      RECT 47.42 2 52.9 2.2 ;
      RECT 43.58 1.16 44.28 1.36 ;
      RECT 43.65 0.74 43.85 1.36 ;
      RECT 43.65 0.74 47.14 0.94 ;
      RECT 27.26 2.84 42.82 3.04 ;
      RECT 27.26 2.34 27.46 3.04 ;
      RECT 10.94 2.84 17.38 3.04 ;
      RECT 17.18 2 17.38 3.04 ;
      RECT 10.94 2.42 11.14 3.04 ;
      RECT 6.14 2.42 11.14 2.62 ;
      RECT 0.38 2.42 2.02 2.62 ;
      RECT 1.82 2 2.02 2.62 ;
      RECT 6.14 2 6.34 2.62 ;
      RECT 17.18 2 17.88 2.2 ;
      RECT 1.82 2 6.34 2.2 ;
      RECT 61.82 2 63.46 2.2 ;
      RECT 44.54 2.84 50.98 3.04 ;
      RECT 29.66 1.16 42.34 1.36 ;
      RECT 12.84 1.16 16.9 1.36 ;
  END
  PROPERTY CatenaDesignType "deviceLevel" ;
END sg13g2_dfrbpq1arx_1

END LIBRARY
